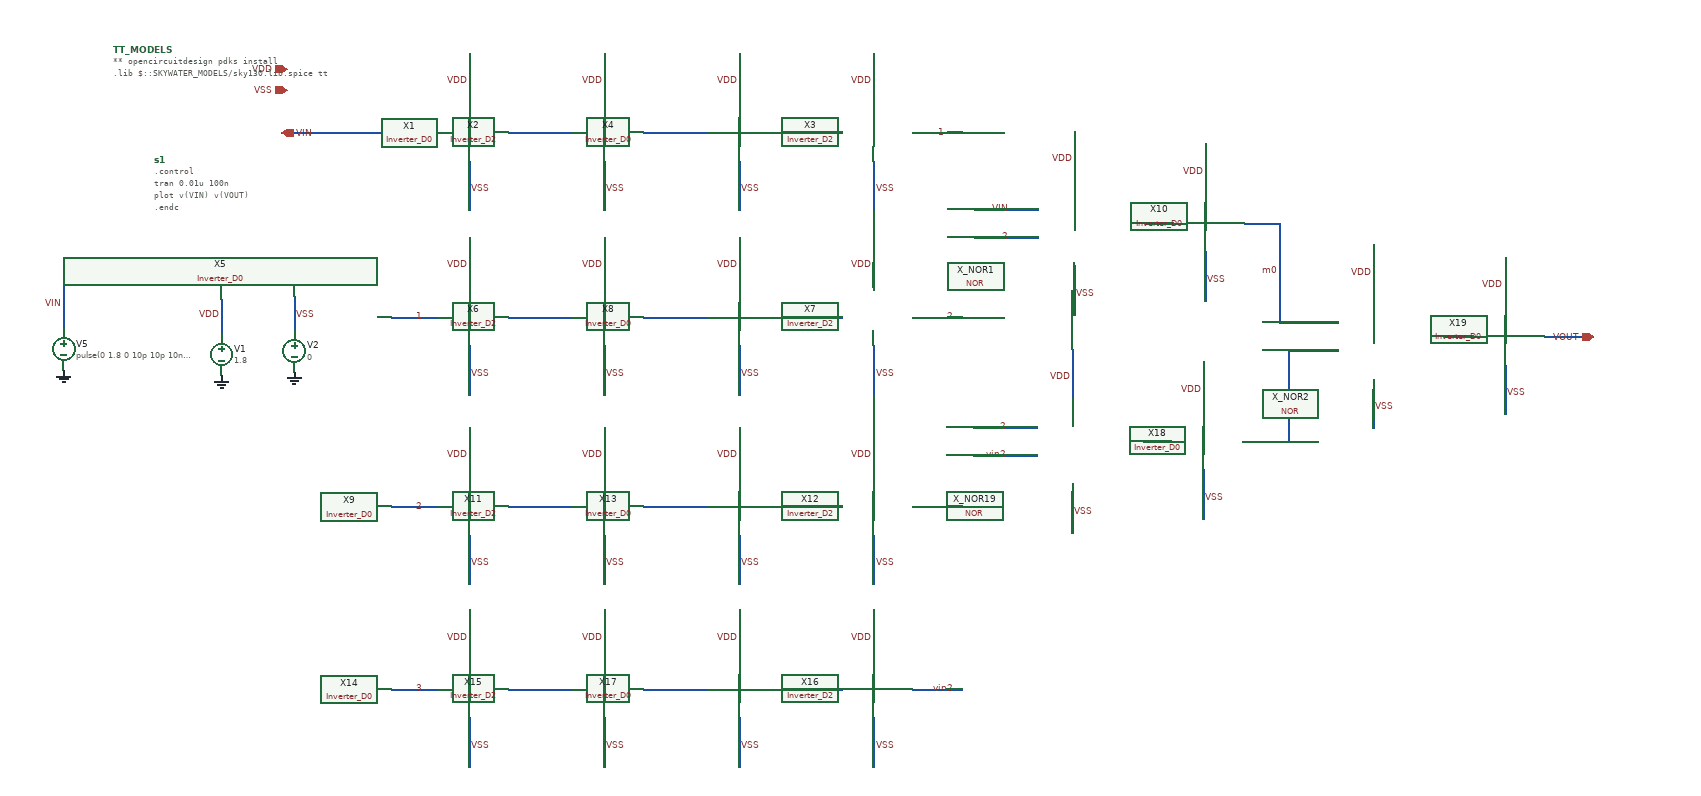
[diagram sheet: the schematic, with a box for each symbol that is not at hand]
v {xschem version=3.0.0 file_version=1.2 }
G {}
K {}
V {}
S {}
E {}
N 1505 -1262.5 1505 -1192.5 {
lab=VDD}
N 1505 -1110 1505 -1040 {
lab=VSS}
N 1560 -1150 1650 -1150 {
lab=#net1}
N 1240 -1150 1390 -1150 {
lab=VIN}
N 2130 -1150 2200 -1150 {
lab=1}
N 1390 -1150 1460 -1150 {
lab=VIN}
N 1695 -1262.5 1695 -1192.5 {
lab=VDD}
N 1695 -1110 1695 -1040 {
lab=VSS}
N 1750 -1150 1840 -1150 {
lab=#net2}
N 2075 -1262.5 2075 -1192.5 {
lab=VDD}
N 2075 -1110 2075 -1040 {
lab=VSS}
N 932.5 -935 932.5 -875 {
lab=VIN}
N 1155 -915 1155 -867.5 {
lab=VDD}
N 1257.5 -920 1257.5 -872.5 {
lab=VSS}
N 1885 -1262.5 1885 -1192.5 {
lab=VDD}
N 1885 -1110 1885 -1040 {
lab=VSS}
N 1940 -1150 2030 -1150 {
lab=#net3}
N 1505 -1002.5 1505 -932.5 {
lab=VDD}
N 1505 -850 1505 -780 {
lab=VSS}
N 1560 -890 1650 -890 {
lab=#net4}
N 1695 -1002.5 1695 -932.5 {
lab=VDD}
N 1695 -850 1695 -780 {
lab=VSS}
N 1750 -890 1840 -890 {
lab=#net5}
N 2075 -1002.5 2075 -932.5 {
lab=VDD}
N 2075 -850 2075 -780 {
lab=VSS}
N 1885 -1002.5 1885 -932.5 {
lab=VDD}
N 1885 -850 1885 -780 {
lab=VSS}
N 1940 -890 2030 -890 {
lab=#net6}
N 1395 -890 1460 -890 {
lab=1}
N 2130 -890 2200 -890 {
lab=2}
N 2457.5 -1022.5 2497.5 -1022.5 {
lab=#net7}
N 2217.5 -1002.5 2307.5 -1002.5 {
lab=2}
N 3020 -862.5 3090 -862.5 {
lab=VOUT}
N 2542.5 -1135 2542.5 -1065 {
lab=VDD}
N 2542.5 -982.5 2542.5 -912.5 {
lab=VSS}
N 2217.5 -1042.5 2307.5 -1042.5 {
lab=VIN}
N 2357.5 -1152.5 2357.5 -1082.5 {
lab=VDD}
N 2357.5 -962.5 2357.5 -892.5 {
lab=VSS}
N 1505 -735 1505 -665 {
lab=VDD}
N 1505 -582.5 1505 -512.5 {
lab=VSS}
N 1560 -622.5 1650 -622.5 {
lab=#net8}
N 1695 -735 1695 -665 {
lab=VDD}
N 1695 -582.5 1695 -512.5 {
lab=VSS}
N 1750 -622.5 1840 -622.5 {
lab=#net9}
N 2075 -735 2075 -665 {
lab=VDD}
N 2075 -582.5 2075 -512.5 {
lab=VSS}
N 1885 -735 1885 -665 {
lab=VDD}
N 1885 -582.5 1885 -512.5 {
lab=VSS}
N 1940 -622.5 2030 -622.5 {
lab=#net10}
N 1395 -622.5 1460 -622.5 {
lab=2}
N 2130 -622.5 2200 -622.5 {
lab=3}
N 1505 -477.5 1505 -407.5 {
lab=VDD}
N 1505 -325 1505 -255 {
lab=VSS}
N 1560 -365 1650 -365 {
lab=#net11}
N 1695 -477.5 1695 -407.5 {
lab=VDD}
N 1695 -325 1695 -255 {
lab=VSS}
N 1750 -365 1840 -365 {
lab=#net12}
N 2075 -477.5 2075 -407.5 {
lab=VDD}
N 2075 -325 2075 -255 {
lab=VSS}
N 1885 -477.5 1885 -407.5 {
lab=VDD}
N 1885 -325 1885 -255 {
lab=VSS}
N 1940 -365 2030 -365 {
lab=#net13}
N 1395 -365 1460 -365 {
lab=3}
N 2130 -365 2200 -365 {
lab=vin2}
N 2455 -715 2495 -715 {
lab=#net14}
N 2215 -695 2305 -695 {
lab=vin2}
N 2540 -827.5 2540 -757.5 {
lab=VDD}
N 2540 -675 2540 -605 {
lab=VSS}
N 2215 -735 2305 -735 {
lab=2}
N 2355 -845 2355 -775 {
lab=VDD}
N 2355 -655 2355 -585 {
lab=VSS}
N 2880 -862.5 2920 -862.5 {
lab=#net15}
N 2965 -975 2965 -905 {
lab=VDD}
N 2965 -822.5 2965 -752.5 {
lab=VSS}
N 2780 -992.5 2780 -922.5 {
lab=VDD}
N 2780 -802.5 2780 -732.5 {
lab=VSS}
N 2595 -715 2660 -715 {
lab=m1}
N 2660 -842.5 2660 -715 {
lab=m1}
N 2660 -842.5 2730 -842.5 {
lab=m1}
N 2597.5 -1022.5 2647.5 -1022.5 {
lab=m0}
N 2647.5 -1022.5 2647.5 -882.5 {
lab=m0}
N 2647.5 -882.5 2730 -882.5 {
lab=m0}
C {devices/lab_wire.sym} 1505 -1222.5 0 0 {name=l1 sig_type=std_logic lab=VDD}
C {devices/lab_wire.sym} 1505 -1070 0 1 {name=l2 sig_type=std_logic lab=VSS}
C {devices/iopin.sym} 1247.5 -1240 0 0 {name=p1 lab=VDD}
C {devices/iopin.sym} 1247.5 -1210 0 0 {name=p2 lab=VSS}
C {devices/iopin.sym} 1240 -1150 0 1 {name=p3 lab=VIN}
C {DC_DC_Converter/DELAY_JAWAD/Inverter_D0.sym} 1420 -1150 0 0 {name=X1}
C {DC_DC_Converter/DELAY_JAWAD/Inverter_D2.sym} 1470 -1150 0 0 {name=X2}
C {devices/lab_wire.sym} 1695 -1222.5 0 0 {name=l3 sig_type=std_logic lab=VDD}
C {devices/lab_wire.sym} 1695 -1070 0 1 {name=l4 sig_type=std_logic lab=VSS}
C {DC_DC_Converter/DELAY_JAWAD/Inverter_D2.sym} 1850 -1150 0 0 {name=X3}
C {devices/lab_wire.sym} 2075 -1222.5 0 0 {name=l5 sig_type=std_logic lab=VDD}
C {devices/lab_wire.sym} 2075 -1070 0 1 {name=l6 sig_type=std_logic lab=VSS}
C {devices/vsource.sym} 932.5 -845 0 0 {name=V5 value="pulse(0 1.8 0 10p 10p 10n 100n 0)"}
C {devices/gnd.sym} 932.5 -815 0 0 {name=l9 lab=GND}
C {devices/vsource.sym} 1155 -837.5 0 0 {name=V1 value=1.8}
C {devices/gnd.sym} 1155 -807.5 0 0 {name=l7 lab=GND}
C {devices/vsource.sym} 1257.5 -842.5 0 0 {name=V2 value=0}
C {devices/gnd.sym} 1257.5 -812.5 0 0 {name=l8 lab=GND}
C {devices/lab_wire.sym} 1155 -892.5 0 0 {name=l10 sig_type=std_logic lab=VDD}
C {devices/lab_wire.sym} 1257.5 -892.5 0 1 {name=l11 sig_type=std_logic lab=VSS}
C {devices/lab_wire.sym} 932.5 -907.5 0 0 {name=l12 sig_type=std_logic lab=VIN}
C {devices/code.sym} 1002.5 -1267.5 0 0 {name=TT_MODELS
only_toplevel=true
format="tcleval( @value )"
value="
** opencircuitdesign pdks install
.lib $::SKYWATER_MODELS/sky130.lib.spice tt

"
spice_ignore=false}
C {devices/code_shown.sym} 1060 -1112.5 0 0 {name=s1 only_toplevel=false value="
.control
tran 0.01u 100n
plot v(VIN) v(VOUT)

.endc
"}
C {devices/lab_wire.sym} 1885 -1222.5 0 0 {name=l15 sig_type=std_logic lab=VDD}
C {devices/lab_wire.sym} 1885 -1070 0 1 {name=l16 sig_type=std_logic lab=VSS}
C {DC_DC_Converter/DELAY_JAWAD/Inverter_D0.sym} 1800 -1150 0 0 {name=X4}
C {devices/lab_wire.sym} 1505 -962.5 0 0 {name=l17 sig_type=std_logic lab=VDD}
C {devices/lab_wire.sym} 1505 -810 0 1 {name=l18 sig_type=std_logic lab=VSS}
C {DC_DC_Converter/DELAY_JAWAD/Inverter_D0.sym} 1420 -890 0 0 {name=X5}
C {DC_DC_Converter/DELAY_JAWAD/Inverter_D2.sym} 1470 -890 0 0 {name=X6}
C {devices/lab_wire.sym} 1695 -962.5 0 0 {name=l19 sig_type=std_logic lab=VDD}
C {devices/lab_wire.sym} 1695 -810 0 1 {name=l20 sig_type=std_logic lab=VSS}
C {DC_DC_Converter/DELAY_JAWAD/Inverter_D2.sym} 1850 -890 0 0 {name=X7}
C {devices/lab_wire.sym} 2075 -962.5 0 0 {name=l21 sig_type=std_logic lab=VDD}
C {devices/lab_wire.sym} 2075 -810 0 1 {name=l22 sig_type=std_logic lab=VSS}
C {devices/lab_wire.sym} 1427.5 -890 0 1 {name=l24 sig_type=std_logic lab=1}
C {devices/lab_wire.sym} 1885 -962.5 0 0 {name=l25 sig_type=std_logic lab=VDD}
C {devices/lab_wire.sym} 1885 -810 0 1 {name=l26 sig_type=std_logic lab=VSS}
C {DC_DC_Converter/DELAY_JAWAD/Inverter_D0.sym} 1800 -890 0 0 {name=X8}
C {devices/lab_wire.sym} 2162.5 -1150 0 1 {name=l27 sig_type=std_logic lab=1}
C {devices/iopin.sym} 3090 -862.5 0 0 {name=p4 lab=VOUT}
C {devices/lab_wire.sym} 2542.5 -1095 0 0 {name=l13 sig_type=std_logic lab=VDD}
C {devices/lab_wire.sym} 2542.5 -942.5 0 1 {name=l14 sig_type=std_logic lab=VSS}
C {DC_DC_Converter/DELAY_JAWAD/Inverter_D0.sym} 2457.5 -1022.5 0 0 {name=X10}
C {devices/lab_wire.sym} 2190 -890 0 0 {name=l23 sig_type=std_logic lab=2}
C {devices/lab_wire.sym} 2267.5 -1002.5 0 0 {name=l28 sig_type=std_logic lab=2}
C {devices/lab_wire.sym} 2267.5 -1042.5 0 0 {name=l29 sig_type=std_logic lab=VIN}
C {DC_DC_Converter/NOR_GATE/NOR.sym} 2287.5 -952.5 0 0 {name=X_NOR1}
C {devices/lab_wire.sym} 2357.5 -1112.5 0 0 {name=l30 sig_type=std_logic lab=VDD}
C {devices/lab_wire.sym} 2357.5 -922.5 0 1 {name=l31 sig_type=std_logic lab=VSS}
C {devices/lab_wire.sym} 1505 -695 0 0 {name=l32 sig_type=std_logic lab=VDD}
C {devices/lab_wire.sym} 1505 -542.5 0 1 {name=l33 sig_type=std_logic lab=VSS}
C {DC_DC_Converter/DELAY_JAWAD/Inverter_D0.sym} 1420 -622.5 0 0 {name=X9}
C {DC_DC_Converter/DELAY_JAWAD/Inverter_D2.sym} 1470 -622.5 0 0 {name=X11}
C {devices/lab_wire.sym} 1695 -695 0 0 {name=l34 sig_type=std_logic lab=VDD}
C {devices/lab_wire.sym} 1695 -542.5 0 1 {name=l35 sig_type=std_logic lab=VSS}
C {DC_DC_Converter/DELAY_JAWAD/Inverter_D2.sym} 1850 -622.5 0 0 {name=X12}
C {devices/lab_wire.sym} 2075 -695 0 0 {name=l36 sig_type=std_logic lab=VDD}
C {devices/lab_wire.sym} 2075 -542.5 0 1 {name=l37 sig_type=std_logic lab=VSS}
C {devices/lab_wire.sym} 1427.5 -622.5 0 1 {name=l38 sig_type=std_logic lab=2}
C {devices/lab_wire.sym} 1885 -695 0 0 {name=l39 sig_type=std_logic lab=VDD}
C {devices/lab_wire.sym} 1885 -542.5 0 1 {name=l40 sig_type=std_logic lab=VSS}
C {DC_DC_Converter/DELAY_JAWAD/Inverter_D0.sym} 1800 -622.5 0 0 {name=X13}
C {devices/lab_wire.sym} 2190 -622.5 0 0 {name=l41 sig_type=std_logic lab=3}
C {devices/lab_wire.sym} 1505 -437.5 0 0 {name=l42 sig_type=std_logic lab=VDD}
C {devices/lab_wire.sym} 1505 -285 0 1 {name=l43 sig_type=std_logic lab=VSS}
C {DC_DC_Converter/DELAY_JAWAD/Inverter_D0.sym} 1420 -365 0 0 {name=X14}
C {DC_DC_Converter/DELAY_JAWAD/Inverter_D2.sym} 1470 -365 0 0 {name=X15}
C {devices/lab_wire.sym} 1695 -437.5 0 0 {name=l44 sig_type=std_logic lab=VDD}
C {devices/lab_wire.sym} 1695 -285 0 1 {name=l45 sig_type=std_logic lab=VSS}
C {DC_DC_Converter/DELAY_JAWAD/Inverter_D2.sym} 1850 -365 0 0 {name=X16}
C {devices/lab_wire.sym} 2075 -437.5 0 0 {name=l46 sig_type=std_logic lab=VDD}
C {devices/lab_wire.sym} 2075 -285 0 1 {name=l47 sig_type=std_logic lab=VSS}
C {devices/lab_wire.sym} 1427.5 -365 0 1 {name=l48 sig_type=std_logic lab=3}
C {devices/lab_wire.sym} 1885 -437.5 0 0 {name=l49 sig_type=std_logic lab=VDD}
C {devices/lab_wire.sym} 1885 -285 0 1 {name=l50 sig_type=std_logic lab=VSS}
C {DC_DC_Converter/DELAY_JAWAD/Inverter_D0.sym} 1800 -365 0 0 {name=X17}
C {devices/lab_wire.sym} 2190 -365 0 0 {name=l51 sig_type=std_logic lab=vin2}
C {devices/lab_wire.sym} 2540 -787.5 0 0 {name=l52 sig_type=std_logic lab=VDD}
C {devices/lab_wire.sym} 2540 -635 0 1 {name=l53 sig_type=std_logic lab=VSS}
C {DC_DC_Converter/DELAY_JAWAD/Inverter_D0.sym} 2455 -715 0 0 {name=X18}
C {devices/lab_wire.sym} 2265 -695 0 0 {name=l54 sig_type=std_logic lab=vin2}
C {devices/lab_wire.sym} 2265 -735 0 0 {name=l55 sig_type=std_logic lab=2}
C {DC_DC_Converter/NOR_GATE/NOR.sym} 2285 -645 0 0 {name=X_NOR19}
C {devices/lab_wire.sym} 2355 -805 0 0 {name=l56 sig_type=std_logic lab=VDD}
C {devices/lab_wire.sym} 2355 -615 0 1 {name=l57 sig_type=std_logic lab=VSS}
C {devices/lab_wire.sym} 2965 -935 0 0 {name=l58 sig_type=std_logic lab=VDD}
C {devices/lab_wire.sym} 2965 -782.5 0 1 {name=l59 sig_type=std_logic lab=VSS}
C {DC_DC_Converter/DELAY_JAWAD/Inverter_D0.sym} 2880 -862.5 0 0 {name=X19}
C {devices/lab_wire.sym} 2780 -952.5 0 0 {name=l62 sig_type=std_logic lab=VDD}
C {devices/lab_wire.sym} 2780 -762.5 0 1 {name=l63 sig_type=std_logic lab=VSS}
C {devices/lab_wire.sym} 2647.5 -955 0 0 {name=l60 sig_type=std_logic lab=m0}
C {devices/lab_wire.sym} 2660 -762.5 0 0 {name=l61 sig_type=std_logic lab=m1}
C {DC_DC_Converter/NOR_GATE/NOR.sym} 2710 -792.5 0 0 {name=X_NOR2}
